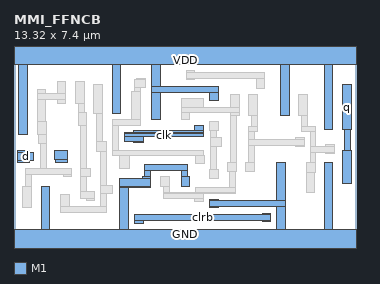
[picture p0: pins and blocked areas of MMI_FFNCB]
MACRO MMI_FFNCB
	CLASS CORE ;
	FOREIGN MMI_FFNCB 0 0 ;
	SIZE 13.32 BY 7.4 ;
	SYMMETRY X Y ;
	SITE CORE1 ;
	PIN d
		DIRECTION input ;
		USE SIGNAL ;
		PORT
			LAYER M1 ;
			RECT 0.145 3.495 0.595 3.555 ;
			LAYER M1 ;
			RECT 0.145 3.155 0.76 3.495 ;
			LAYER M1 ;
			RECT 0.145 3.105 0.595 3.155 ;
		END
		AntennaGateArea 0.4968 ;
	END d
	PIN GND
		DIRECTION inout ;
		USE GROUND ;
		PORT
			LAYER M1 ;
			RECT 5.1 2.79 6.74 3.02 ;
			LAYER M1 ;
			RECT 5.1 2.56 5.33 2.79 ;
			LAYER M1 ;
			RECT 4.1 2.48 4.48 2.49 ;
			LAYER M1 ;
			RECT 4.99 2.48 5.33 2.56 ;
			LAYER M1 ;
			RECT 1.06 0.5 1.4 2.175 ;
			LAYER M1 ;
			RECT 4.1 2.15 5.33 2.48 ;
			LAYER M1 ;
			RECT 6.51 2.56 6.74 2.79 ;
			LAYER M1 ;
			RECT 6.51 2.18 6.85 2.56 ;
			LAYER M1 ;
			RECT 4.115 2.14 5.33 2.15 ;
			LAYER M1 ;
			RECT 4.115 0.5 4.455 2.14 ;
			LAYER M1 ;
			RECT 7.61 1.605 7.95 1.665 ;
			LAYER M1 ;
			RECT 10.23 1.605 10.57 3.095 ;
			LAYER M1 ;
			RECT 7.61 1.375 10.57 1.605 ;
			LAYER M1 ;
			RECT 7.61 1.325 7.95 1.375 ;
			LAYER M1 ;
			RECT 10.23 0.5 10.57 1.375 ;
			LAYER M1 ;
			RECT 12.08 0.5 12.42 3.105 ;
			LAYER M1 ;
			RECT 0 -0.5 13.32 0.5 ;
		END
	END GND
	PIN q
		DIRECTION output ;
		USE SIGNAL ;
		PORT
			LAYER M1 ;
			RECT 12.8 4.365 13.14 6.125 ;
			LAYER M1 ;
			RECT 12.86 3.555 13.09 4.365 ;
			LAYER M1 ;
			RECT 12.8 2.265 13.14 3.555 ;
		END
		AntennaDiffArea 1.3248 ;
	END q
	PIN VDD
		DIRECTION inout ;
		USE POWER ;
		PORT
			LAYER M1 ;
			RECT 0 6.9 13.32 7.9 ;
			LAYER M1 ;
			RECT 0.18 4.19 0.52 6.9 ;
			LAYER M1 ;
			RECT 3.825 5.015 4.165 6.9 ;
			LAYER M1 ;
			RECT 5.36 6.055 5.7 6.9 ;
			LAYER M1 ;
			RECT 5.36 5.825 7.955 6.055 ;
			LAYER M1 ;
			RECT 5.36 4.79 5.7 5.825 ;
			LAYER M1 ;
			RECT 7.615 5.495 7.955 5.825 ;
			LAYER M1 ;
			RECT 10.38 4.91 10.72 6.9 ;
			LAYER M1 ;
			RECT 12.08 4.365 12.42 6.9 ;
		END
	END VDD
	PIN clk
		DIRECTION input ;
		USE CLOCK ;
		PORT
			LAYER M1 ;
			RECT 7.045 4.325 7.385 4.555 ;
			LAYER M1 ;
			RECT 4.64 4.255 7.385 4.325 ;
			LAYER M1 ;
			RECT 4.3 4.215 7.385 4.255 ;
			LAYER M1 ;
			RECT 4.3 4.095 7.375 4.215 ;
			LAYER M1 ;
			RECT 4.3 3.915 5.04 4.095 ;
			LAYER M1 ;
			RECT 4.64 3.88 5.04 3.915 ;
		END
		AntennaGateArea 0.6408 ;
	END clk
	PIN clrb
		DIRECTION input ;
		USE SIGNAL ;
		PORT
			LAYER M1 ;
			RECT 1.58 3.215 2.075 3.555 ;
			LAYER M1 ;
			RECT 1.625 3.105 2.075 3.215 ;
			LAYER M1 ;
			RECT 4.695 1.055 5.035 1.07 ;
			LAYER M1 ;
			RECT 9.66 1.055 10 1.12 ;
			LAYER M1 ;
			RECT 4.695 0.825 10 1.055 ;
			LAYER M1 ;
			RECT 4.695 0.73 5.035 0.825 ;
			LAYER M1 ;
			RECT 9.66 0.78 10 0.825 ;
		END
		AntennaGateArea 0.7128 ;
	END clrb
	OBS
		LAYER M1 ;
		RECT 0.9 5.785 1.24 5.95 ;
		LAYER M1 ;
		RECT 1.685 5.785 2.025 6.25 ;
		LAYER M1 ;
		RECT 0.9 5.555 2.025 5.785 ;
		LAYER M1 ;
		RECT 0.9 4.685 1.24 5.555 ;
		LAYER M1 ;
		RECT 1.685 5.41 2.025 5.555 ;
		LAYER M1 ;
		RECT 2.405 5.41 2.745 6.25 ;
		LAYER M1 ;
		RECT 2.515 5.05 2.745 5.41 ;
		LAYER M1 ;
		RECT 0.9 4.19 1.27 4.685 ;
		LAYER M1 ;
		RECT 2.515 4.54 2.82 5.05 ;
		LAYER M1 ;
		RECT 3.105 5.015 3.445 6.135 ;
		LAYER M1 ;
		RECT 4.79 6.34 5.13 6.375 ;
		LAYER M1 ;
		RECT 4.695 6.035 5.13 6.34 ;
		LAYER M1 ;
		RECT 6.7 6.61 7.04 6.67 ;
		LAYER M1 ;
		RECT 6.7 6.38 9.77 6.61 ;
		LAYER M1 ;
		RECT 6.7 6.33 7.04 6.38 ;
		LAYER M1 ;
		RECT 4.695 5.85 4.925 6.035 ;
		LAYER M1 ;
		RECT 0.96 3.825 1.27 4.19 ;
		LAYER M1 ;
		RECT 1.04 2.875 1.27 3.825 ;
		LAYER M1 ;
		RECT 2.59 2.875 2.82 4.54 ;
		LAYER M1 ;
		RECT 3.215 3.925 3.445 5.015 ;
		LAYER M1 ;
		RECT 4.585 4.785 4.925 5.85 ;
		LAYER M1 ;
		RECT 9.43 5.985 9.77 6.38 ;
		LAYER M1 ;
		RECT 6.51 5.255 7.385 5.595 ;
		LAYER M1 ;
		RECT 8.425 5.255 8.765 5.75 ;
		LAYER M1 ;
		RECT 6.51 5.025 8.765 5.255 ;
		LAYER M1 ;
		RECT 6.51 4.785 6.85 5.025 ;
		LAYER M1 ;
		RECT 8.425 4.91 8.765 5.025 ;
		LAYER M1 ;
		RECT 9.145 4.91 9.485 5.75 ;
		LAYER M1 ;
		RECT 11.1 4.91 11.44 5.75 ;
		LAYER M1 ;
		RECT 3.84 4.555 4.925 4.785 ;
		LAYER M1 ;
		RECT 3.215 3.51 3.61 3.925 ;
		LAYER M1 ;
		RECT 0.45 2.645 2.25 2.875 ;
		LAYER M1 ;
		RECT 0.45 2.175 0.68 2.645 ;
		LAYER M1 ;
		RECT 1.91 2.535 2.25 2.645 ;
		LAYER M1 ;
		RECT 2.59 2.535 2.97 2.875 ;
		LAYER M1 ;
		RECT 0.34 1.335 0.68 2.175 ;
		LAYER M1 ;
		RECT 2.59 1.95 2.82 2.535 ;
		LAYER M1 ;
		RECT 3.38 2.21 3.61 3.51 ;
		LAYER M1 ;
		RECT 3.84 3.58 4.07 4.555 ;
		LAYER M1 ;
		RECT 7.615 4.345 7.955 4.685 ;
		LAYER M1 ;
		RECT 7.67 4.055 7.9 4.345 ;
		LAYER M1 ;
		RECT 7.67 3.715 8.065 4.055 ;
		LAYER M1 ;
		RECT 3.84 3.385 7.385 3.58 ;
		LAYER M1 ;
		RECT 3.84 3.35 7.42 3.385 ;
		LAYER M1 ;
		RECT 4.1 2.87 4.48 3.35 ;
		LAYER M1 ;
		RECT 7.08 3.045 7.42 3.35 ;
		LAYER M1 ;
		RECT 7.67 2.815 7.9 3.715 ;
		LAYER M1 ;
		RECT 8.425 3.095 8.655 4.91 ;
		LAYER M1 ;
		RECT 9.255 4.515 9.485 4.91 ;
		LAYER M1 ;
		RECT 9.145 4.285 9.485 4.515 ;
		LAYER M1 ;
		RECT 11.21 4.515 11.44 4.91 ;
		LAYER M1 ;
		RECT 11.21 4.285 11.76 4.515 ;
		LAYER M1 ;
		RECT 9.145 4.005 9.375 4.285 ;
		LAYER M1 ;
		RECT 10.96 4.005 11.3 4.055 ;
		LAYER M1 ;
		RECT 9.145 3.775 11.3 4.005 ;
		LAYER M1 ;
		RECT 9.145 3.095 9.375 3.775 ;
		LAYER M1 ;
		RECT 10.96 3.715 11.3 3.775 ;
		LAYER M1 ;
		RECT 11.53 3.735 11.76 4.285 ;
		LAYER M1 ;
		RECT 12.14 3.735 12.48 3.78 ;
		LAYER M1 ;
		RECT 11.53 3.505 12.48 3.735 ;
		LAYER M1 ;
		RECT 11.53 3.095 11.76 3.505 ;
		LAYER M1 ;
		RECT 12.14 3.44 12.48 3.505 ;
		LAYER M1 ;
		RECT 1.82 1.38 2.16 1.855 ;
		LAYER M1 ;
		RECT 2.59 1.71 3.15 1.95 ;
		LAYER M1 ;
		RECT 2.81 1.61 3.15 1.71 ;
		LAYER M1 ;
		RECT 3.38 1.87 3.855 2.21 ;
		LAYER M1 ;
		RECT 5.71 2.18 6.05 2.56 ;
		LAYER M1 ;
		RECT 7.61 2.475 7.95 2.815 ;
		LAYER M1 ;
		RECT 8.315 2.755 8.655 3.095 ;
		LAYER M1 ;
		RECT 9.035 2.755 9.375 3.095 ;
		LAYER M1 ;
		RECT 3.38 1.38 3.61 1.87 ;
		LAYER M1 ;
		RECT 1.82 1.15 3.61 1.38 ;
		LAYER M1 ;
		RECT 5.815 1.93 6.045 2.18 ;
		LAYER M1 ;
		RECT 8.4 2.13 8.63 2.755 ;
		LAYER M1 ;
		RECT 7.08 1.93 8.63 2.13 ;
		LAYER M1 ;
		RECT 5.815 1.9 8.63 1.93 ;
		LAYER M1 ;
		RECT 5.815 1.7 7.38 1.9 ;
		LAYER M1 ;
		RECT 7.04 1.565 7.38 1.7 ;
		LAYER M1 ;
		RECT 11.38 2.715 11.76 3.095 ;
		LAYER M1 ;
		RECT 11.38 1.935 11.72 2.715 ;
	END
END MMI_FFNCB
